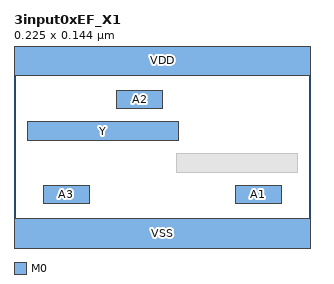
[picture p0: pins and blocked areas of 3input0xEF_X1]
MACRO 3input0xEF_X1
  CLASS CORE ;
  ORIGIN 0 0 ;
  FOREIGN 3input0xEF_X1 0 0 ;
  SIZE 0.2250 BY 0.1440 ;
  SYMMETRY X Y ;
  SITE coresite ;
  PIN A1
    DIRECTION INPUT ;
    USE SIGNAL ;
    PORT
      LAYER M0 ;
        RECT 0.1680 0.0290 0.2025 0.0430 ;
    END
  END A1
  PIN A2
    DIRECTION INPUT ;
    USE SIGNAL ;
    PORT
      LAYER M0 ;
        RECT 0.0780 0.1010 0.1125 0.1150 ;
    END
  END A2
  PIN A3
    DIRECTION INPUT ;
    USE SIGNAL ;
    PORT
      LAYER M0 ;
        RECT 0.0225 0.0290 0.0570 0.0430 ;
    END
  END A3
  PIN Y
    DIRECTION OUTPUT ;
    USE SIGNAL ;
    PORT
      LAYER M0 ;
        RECT 0.0105 0.0770 0.1245 0.0910 ;
    END
  END Y
  PIN VDD
    DIRECTION INOUT ;
    USE POWER ;
    SHAPE ABUTMENT ;
    PORT
      LAYER M0 ;
        RECT 0.0000 0.1260 0.2250 0.1620 ;
    END
  END VDD
  PIN VSS
    DIRECTION INOUT ;
    USE GROUND ;
    SHAPE ABUTMENT ;
    PORT
      LAYER M0 ;
        RECT 0.0000 -0.0180 0.2250 0.0180 ;
    END
  END VSS
  OBS
    LAYER M0 ;
      RECT 0.1230 0.0530 0.2145 0.0670 ;
  END
END 3input0xEF_X1
